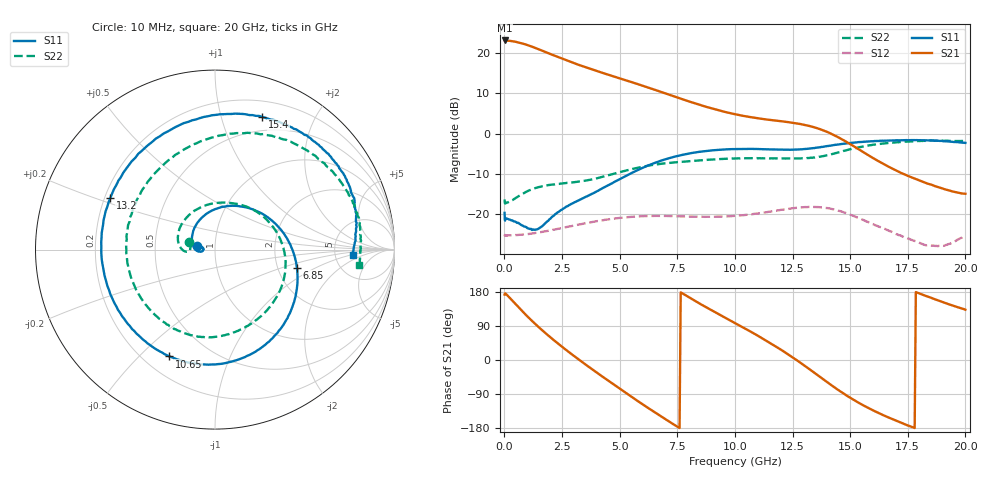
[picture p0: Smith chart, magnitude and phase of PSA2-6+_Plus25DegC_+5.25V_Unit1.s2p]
!Keysight Technologies,N5242A,MY47200155,A.10.49.08
!Date: Thursday, October 19, 2023 15:18:16
!Correction: S11(Full 2 Port(1,2))
!S21(Full 2 Port(1,2))
!S12(Full 2 Port(1,2))
!S22(Full 2 Port(1,2))
!S2P File: Measurements: S11, S21, S12, S22:
# Hz S  dB  R 50
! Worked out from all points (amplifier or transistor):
!   408 points, 10 MHz to 20 GHz, reference 50 ohm
!   highest |S21| = 23.0 dB at 20 MHz (marker M1)
!   |S21| within 3 dB of that: start of sweep to 1.84 GHz
!   unconditionally stable (mu >= 1): start of sweep to end of sweep
!   at 3.05 GHz: K = 1.10, MAG = 18.1 dB, |S12| = -22.7 dB
!   at 9.85 GHz: K = 1.28, MAG = 9.5 dB, |S12| = -20.4 dB
!   at 20 GHz: K = 6.87, MAG = -6.2 dB, |S12| = -25.3 dB
!   S11 on the Smith chart (normalised r, x): 10 MHz: 0.81, +0.03; 6.85 GHz: 2.56, -0.66; 10.65 GHz: 0.30, -0.62; 13.2 GHz: 0.22, +0.22; 15.4 GHz: 0.35, +1.36; 20 GHz: 7.44, -1.03
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1e7  -19.61 168.5  23.04 172.7  -25.41 -2.7  -16.28 164.0
2e7  -21.27 172.4  23.04 175.4  -25.08 -0.7  -17.12 169.9
3.5e8  -21.46 172.8  22.85 156.1  -25.17 -4.8  -16.46 -175.8
7e8  -22.46 170.1  22.42 133.5  -25.04 -9.6  -15.18 -177.7
1.25e9  -23.73 177.0  21.39 100.2  -24.67 -17.6  -13.66 169.4
1.75e9  -22.34 -172.0  20.25 72.6  -24.20 -25.6  -12.90 153.4
2.25e9  -19.80 -176.6  19.10 47.1  -23.65 -34.5  -12.51 135.3
2.75e9  -17.93 167.3  18.00 23.1  -23.07 -44.7  -12.20 116.0
3.35e9  -16.16 142.9  16.75 -4.3  -22.38 -58.2  -11.78 92.2
4.05e9  -14.17 110.0  15.40 -35.1  -21.63 -75.1  -11.02 65.0
4.8e9  -11.88 72.8  14.03 -67.2  -20.99 -94.9  -9.85 37.2
5.8e9  -8.99 27.4  12.22 -108.9  -20.49 -122.5  -8.44 2.7
6.7e9  -6.90 -7.3  10.50 -145.1  -20.37 -146.9  -7.54 -25.2
6.85e9  -6.60 -12.4  10.21 -150.9  -20.37 -150.9  -7.43 -29.5
8.4e9  -4.57 -58.3  7.24 151.3  -20.57 169.6  -6.66 -69.0
1.005e10  -3.82 -98.1  4.73 95.9  -20.30 132.3  -6.15 -99.4
1.065e10  -3.78 -113.1  4.10 76.0  -20.01 118.2  -6.09 -110.6
1.32e10  -3.74 153.9  1.93 -22.7  -18.15 42.5  -6.05 169.0
1.335e10  -3.65 146.8  1.71 -29.5  -18.14 37.1  -6.01 161.7
1.54e10  -2.10 70.4  -3.97 -113.9  -20.95 -34.5  -3.36 73.0
1.67e10  -1.72 44.6  -8.27 -152.5  -24.09 -66.4  -2.33 42.1
2e10  -2.30 -2.1  -14.89 132.8  -25.29 -98.5  -1.86 -6.1
